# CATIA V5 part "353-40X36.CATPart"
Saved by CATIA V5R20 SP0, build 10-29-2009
Part number: 353-40X36
Definition: NONE
Nomenclature: 353-40X36
Source: Unknown
Description: 353-40X36
Bounding box of the stored display mesh (mm): x -8 to 28, y -26 to 26, z -26 to 26
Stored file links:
  C:\Users\Utente\Desktop\IO LAVORO\3D X SITO CF\X SITO\PLASTICA\353\353-40X36.CATPart

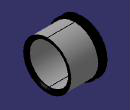
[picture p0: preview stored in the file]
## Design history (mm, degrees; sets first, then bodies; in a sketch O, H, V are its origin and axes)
Body1 "353-40X36" (main body)
  Solid1: solid without history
